VERSION 5.7 ;
  NOWIREEXTENSIONATPIN ON ;
  DIVIDERCHAR "/" ;
  BUSBITCHARS "[]" ;
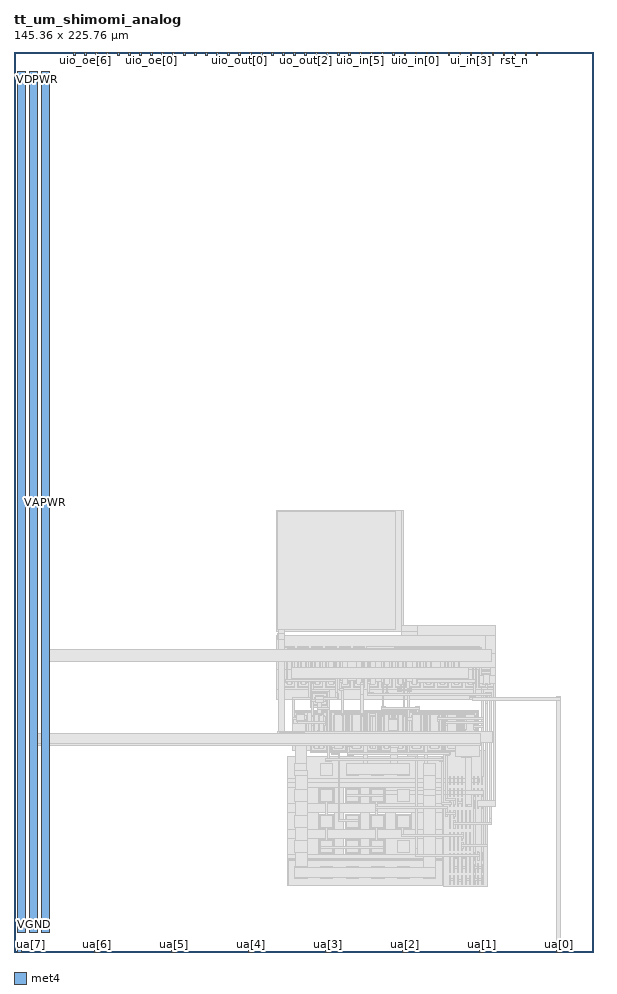
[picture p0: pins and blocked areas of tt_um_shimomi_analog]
MACRO tt_um_shimomi_analog
  CLASS BLOCK ;
  FOREIGN tt_um_shimomi_analog ;
  ORIGIN 0.000 0.000 ;
  SIZE 145.360 BY 225.760 ;
  PIN clk
    DIRECTION INPUT ;
    USE SIGNAL ;
    PORT
      LAYER met4 ;
        RECT 128.190 224.760 128.490 225.760 ;
    END
  END clk
  PIN ena
    DIRECTION INPUT ;
    USE SIGNAL ;
    PORT
      LAYER met4 ;
        RECT 130.950 224.760 131.250 225.760 ;
    END
  END ena
  PIN rst_n
    DIRECTION INPUT ;
    USE SIGNAL ;
    PORT
      LAYER met4 ;
        RECT 125.430 224.760 125.730 225.760 ;
    END
  END rst_n
  PIN ua[0]
    DIRECTION INOUT ;
    USE SIGNAL ;
    PORT
      LAYER met4 ;
        RECT 136.170 0.000 137.070 1.000 ;
    END
  END ua[0]
  PIN ua[1]
    DIRECTION INOUT ;
    USE SIGNAL ;
    PORT
      LAYER met4 ;
        RECT 116.850 0.000 117.750 1.000 ;
    END
  END ua[1]
  PIN ua[2]
    DIRECTION INOUT ;
    USE SIGNAL ;
    PORT
      LAYER met4 ;
        RECT 97.530 0.000 98.430 1.000 ;
    END
  END ua[2]
  PIN ua[3]
    DIRECTION INOUT ;
    USE SIGNAL ;
    PORT
      LAYER met4 ;
        RECT 78.210 0.000 79.110 1.000 ;
    END
  END ua[3]
  PIN ua[4]
    DIRECTION INOUT ;
    USE SIGNAL ;
    PORT
      LAYER met4 ;
        RECT 58.890 0.000 59.790 1.000 ;
    END
  END ua[4]
  PIN ua[5]
    DIRECTION INOUT ;
    USE SIGNAL ;
    PORT
      LAYER met4 ;
        RECT 39.570 0.000 40.470 1.000 ;
    END
  END ua[5]
  PIN ua[6]
    DIRECTION INOUT ;
    USE SIGNAL ;
    PORT
      LAYER met4 ;
        RECT 20.250 0.000 21.150 1.000 ;
    END
  END ua[6]
  PIN ua[7]
    DIRECTION INOUT ;
    USE SIGNAL ;
    PORT
      LAYER met4 ;
        RECT 0.930 0.000 1.830 1.000 ;
    END
  END ua[7]
  PIN ui_in[0]
    DIRECTION INPUT ;
    USE SIGNAL ;
    PORT
      LAYER met4 ;
        RECT 122.670 224.760 122.970 225.760 ;
    END
  END ui_in[0]
  PIN ui_in[1]
    DIRECTION INPUT ;
    USE SIGNAL ;
    PORT
      LAYER met4 ;
        RECT 119.910 224.760 120.210 225.760 ;
    END
  END ui_in[1]
  PIN ui_in[2]
    DIRECTION INPUT ;
    USE SIGNAL ;
    PORT
      LAYER met4 ;
        RECT 117.150 224.760 117.450 225.760 ;
    END
  END ui_in[2]
  PIN ui_in[3]
    DIRECTION INPUT ;
    USE SIGNAL ;
    PORT
      LAYER met4 ;
        RECT 114.390 224.760 114.690 225.760 ;
    END
  END ui_in[3]
  PIN ui_in[4]
    DIRECTION INPUT ;
    USE SIGNAL ;
    PORT
      LAYER met4 ;
        RECT 111.630 224.760 111.930 225.760 ;
    END
  END ui_in[4]
  PIN ui_in[5]
    DIRECTION INPUT ;
    USE SIGNAL ;
    PORT
      LAYER met4 ;
        RECT 108.870 224.760 109.170 225.760 ;
    END
  END ui_in[5]
  PIN ui_in[6]
    DIRECTION INPUT ;
    USE SIGNAL ;
    PORT
      LAYER met4 ;
        RECT 106.110 224.760 106.410 225.760 ;
    END
  END ui_in[6]
  PIN ui_in[7]
    DIRECTION INPUT ;
    USE SIGNAL ;
    PORT
      LAYER met4 ;
        RECT 103.350 224.760 103.650 225.760 ;
    END
  END ui_in[7]
  PIN uio_in[0]
    DIRECTION INPUT ;
    USE SIGNAL ;
    PORT
      LAYER met4 ;
        RECT 100.590 224.760 100.890 225.760 ;
    END
  END uio_in[0]
  PIN uio_in[1]
    DIRECTION INPUT ;
    USE SIGNAL ;
    PORT
      LAYER met4 ;
        RECT 97.830 224.760 98.130 225.760 ;
    END
  END uio_in[1]
  PIN uio_in[2]
    DIRECTION INPUT ;
    USE SIGNAL ;
    PORT
      LAYER met4 ;
        RECT 95.070 224.760 95.370 225.760 ;
    END
  END uio_in[2]
  PIN uio_in[3]
    DIRECTION INPUT ;
    USE SIGNAL ;
    PORT
      LAYER met4 ;
        RECT 92.310 224.760 92.610 225.760 ;
    END
  END uio_in[3]
  PIN uio_in[4]
    DIRECTION INPUT ;
    USE SIGNAL ;
    PORT
      LAYER met4 ;
        RECT 89.550 224.760 89.850 225.760 ;
    END
  END uio_in[4]
  PIN uio_in[5]
    DIRECTION INPUT ;
    USE SIGNAL ;
    PORT
      LAYER met4 ;
        RECT 86.790 224.760 87.090 225.760 ;
    END
  END uio_in[5]
  PIN uio_in[6]
    DIRECTION INPUT ;
    USE SIGNAL ;
    PORT
      LAYER met4 ;
        RECT 84.030 224.760 84.330 225.760 ;
    END
  END uio_in[6]
  PIN uio_in[7]
    DIRECTION INPUT ;
    USE SIGNAL ;
    PORT
      LAYER met4 ;
        RECT 81.270 224.760 81.570 225.760 ;
    END
  END uio_in[7]
  PIN uio_oe[0]
    DIRECTION OUTPUT ;
    USE SIGNAL ;
    PORT
      LAYER met4 ;
        RECT 34.350 224.760 34.650 225.760 ;
    END
  END uio_oe[0]
  PIN uio_oe[1]
    DIRECTION OUTPUT ;
    USE SIGNAL ;
    PORT
      LAYER met4 ;
        RECT 31.590 224.760 31.890 225.760 ;
    END
  END uio_oe[1]
  PIN uio_oe[2]
    DIRECTION OUTPUT ;
    USE SIGNAL ;
    PORT
      LAYER met4 ;
        RECT 28.830 224.760 29.130 225.760 ;
    END
  END uio_oe[2]
  PIN uio_oe[3]
    DIRECTION OUTPUT ;
    USE SIGNAL ;
    PORT
      LAYER met4 ;
        RECT 26.070 224.760 26.370 225.760 ;
    END
  END uio_oe[3]
  PIN uio_oe[4]
    DIRECTION OUTPUT ;
    USE SIGNAL ;
    PORT
      LAYER met4 ;
        RECT 23.310 224.760 23.610 225.760 ;
    END
  END uio_oe[4]
  PIN uio_oe[5]
    DIRECTION OUTPUT ;
    USE SIGNAL ;
    PORT
      LAYER met4 ;
        RECT 20.550 224.760 20.850 225.760 ;
    END
  END uio_oe[5]
  PIN uio_oe[6]
    DIRECTION OUTPUT ;
    USE SIGNAL ;
    PORT
      LAYER met4 ;
        RECT 17.790 224.760 18.090 225.760 ;
    END
  END uio_oe[6]
  PIN uio_oe[7]
    DIRECTION OUTPUT ;
    USE SIGNAL ;
    PORT
      LAYER met4 ;
        RECT 15.030 224.760 15.330 225.760 ;
    END
  END uio_oe[7]
  PIN uio_out[0]
    DIRECTION OUTPUT ;
    USE SIGNAL ;
    PORT
      LAYER met4 ;
        RECT 56.430 224.760 56.730 225.760 ;
    END
  END uio_out[0]
  PIN uio_out[1]
    DIRECTION OUTPUT ;
    USE SIGNAL ;
    PORT
      LAYER met4 ;
        RECT 53.670 224.760 53.970 225.760 ;
    END
  END uio_out[1]
  PIN uio_out[2]
    DIRECTION OUTPUT ;
    USE SIGNAL ;
    PORT
      LAYER met4 ;
        RECT 50.910 224.760 51.210 225.760 ;
    END
  END uio_out[2]
  PIN uio_out[3]
    DIRECTION OUTPUT ;
    USE SIGNAL ;
    PORT
      LAYER met4 ;
        RECT 48.150 224.760 48.450 225.760 ;
    END
  END uio_out[3]
  PIN uio_out[4]
    DIRECTION OUTPUT ;
    USE SIGNAL ;
    PORT
      LAYER met4 ;
        RECT 45.390 224.760 45.690 225.760 ;
    END
  END uio_out[4]
  PIN uio_out[5]
    DIRECTION OUTPUT ;
    USE SIGNAL ;
    PORT
      LAYER met4 ;
        RECT 42.630 224.760 42.930 225.760 ;
    END
  END uio_out[5]
  PIN uio_out[6]
    DIRECTION OUTPUT ;
    USE SIGNAL ;
    PORT
      LAYER met4 ;
        RECT 39.870 224.760 40.170 225.760 ;
    END
  END uio_out[6]
  PIN uio_out[7]
    DIRECTION OUTPUT ;
    USE SIGNAL ;
    PORT
      LAYER met4 ;
        RECT 37.110 224.760 37.410 225.760 ;
    END
  END uio_out[7]
  PIN uo_out[0]
    DIRECTION OUTPUT ;
    USE SIGNAL ;
    PORT
      LAYER met4 ;
        RECT 78.510 224.760 78.810 225.760 ;
    END
  END uo_out[0]
  PIN uo_out[1]
    DIRECTION OUTPUT ;
    USE SIGNAL ;
    PORT
      LAYER met4 ;
        RECT 75.750 224.760 76.050 225.760 ;
    END
  END uo_out[1]
  PIN uo_out[2]
    DIRECTION OUTPUT ;
    USE SIGNAL ;
    PORT
      LAYER met4 ;
        RECT 72.990 224.760 73.290 225.760 ;
    END
  END uo_out[2]
  PIN uo_out[3]
    DIRECTION OUTPUT ;
    USE SIGNAL ;
    PORT
      LAYER met4 ;
        RECT 70.230 224.760 70.530 225.760 ;
    END
  END uo_out[3]
  PIN uo_out[4]
    DIRECTION OUTPUT ;
    USE SIGNAL ;
    PORT
      LAYER met4 ;
        RECT 67.470 224.760 67.770 225.760 ;
    END
  END uo_out[4]
  PIN uo_out[5]
    DIRECTION OUTPUT ;
    USE SIGNAL ;
    PORT
      LAYER met4 ;
        RECT 64.710 224.760 65.010 225.760 ;
    END
  END uo_out[5]
  PIN uo_out[6]
    DIRECTION OUTPUT ;
    USE SIGNAL ;
    PORT
      LAYER met4 ;
        RECT 61.950 224.760 62.250 225.760 ;
    END
  END uo_out[6]
  PIN uo_out[7]
    DIRECTION OUTPUT ;
    USE SIGNAL ;
    PORT
      LAYER met4 ;
        RECT 59.190 224.760 59.490 225.760 ;
    END
  END uo_out[7]
  PIN VDPWR
    DIRECTION INOUT ;
    USE POWER ;
    PORT
      LAYER met4 ;
        RECT 1.000 5.000 3.000 220.760 ;
    END
  END VDPWR
  PIN VGND
    DIRECTION INOUT ;
    USE GROUND ;
    PORT
      LAYER met4 ;
        RECT 4.000 5.000 6.000 220.760 ;
    END
  END VGND
  PIN VAPWR
    DIRECTION INOUT ;
    USE POWER ;
    PORT
      LAYER met4 ;
        RECT 7.000 5.000 9.000 220.760 ;
    END
  END VAPWR
  OBS
      LAYER nwell ;
        RECT 65.750 70.900 120.750 79.430 ;
        RECT 65.750 65.930 120.830 70.900 ;
        RECT 65.750 63.430 120.750 65.930 ;
        RECT 74.250 61.430 78.830 63.430 ;
      LAYER pwell ;
        RECT 69.750 60.430 74.030 60.610 ;
        RECT 74.250 60.430 78.820 60.610 ;
        RECT 69.750 50.430 78.820 60.430 ;
        RECT 74.250 50.030 78.820 50.430 ;
        RECT 79.250 50.030 83.530 60.610 ;
        RECT 83.750 50.030 88.030 60.610 ;
        RECT 88.250 50.030 91.530 60.610 ;
        RECT 91.750 50.030 95.030 60.610 ;
        RECT 95.250 50.030 98.530 60.610 ;
        RECT 98.750 50.030 103.030 60.610 ;
        RECT 103.250 50.030 107.530 60.610 ;
        RECT 107.750 50.430 112.030 60.610 ;
        RECT 112.250 50.430 116.530 60.610 ;
        RECT 68.580 48.365 107.480 49.130 ;
        RECT 68.580 43.195 69.345 48.365 ;
        RECT 74.515 43.195 75.785 48.365 ;
        RECT 80.955 43.195 82.225 48.365 ;
        RECT 87.395 43.195 88.665 48.365 ;
        RECT 93.835 43.195 95.105 48.365 ;
        RECT 100.275 43.195 101.545 48.365 ;
        RECT 106.715 43.195 107.480 48.365 ;
        RECT 68.580 42.610 107.480 43.195 ;
        RECT 68.580 41.865 107.530 42.610 ;
        RECT 68.580 41.860 95.115 41.865 ;
        RECT 68.580 41.845 75.785 41.860 ;
        RECT 68.580 36.675 69.345 41.845 ;
        RECT 74.515 36.690 75.785 41.845 ;
        RECT 80.955 36.690 82.225 41.860 ;
        RECT 87.395 36.690 88.665 41.860 ;
        RECT 93.835 36.695 95.115 41.860 ;
        RECT 100.285 41.845 107.530 41.865 ;
        RECT 100.285 36.695 101.595 41.845 ;
        RECT 93.835 36.690 101.595 36.695 ;
        RECT 74.515 36.675 101.595 36.690 ;
        RECT 106.765 36.675 107.530 41.845 ;
        RECT 68.580 35.420 107.530 36.675 ;
        RECT 68.580 35.405 75.785 35.420 ;
        RECT 68.580 30.235 69.345 35.405 ;
        RECT 74.515 30.250 75.785 35.405 ;
        RECT 80.955 30.250 82.235 35.420 ;
        RECT 87.405 30.250 88.675 35.420 ;
        RECT 93.845 35.415 107.530 35.420 ;
        RECT 93.845 30.250 95.115 35.415 ;
        RECT 74.515 30.245 95.115 30.250 ;
        RECT 100.285 35.405 107.530 35.415 ;
        RECT 100.285 30.245 101.595 35.405 ;
        RECT 74.515 30.235 101.595 30.245 ;
        RECT 106.765 30.235 107.530 35.405 ;
        RECT 68.580 28.980 107.530 30.235 ;
        RECT 68.580 28.965 75.785 28.980 ;
        RECT 68.580 23.795 69.345 28.965 ;
        RECT 74.515 23.810 75.785 28.965 ;
        RECT 80.955 23.810 82.225 28.980 ;
        RECT 87.395 23.810 88.665 28.980 ;
        RECT 93.835 28.965 107.530 28.980 ;
        RECT 93.835 23.810 95.115 28.965 ;
        RECT 74.515 23.795 95.115 23.810 ;
        RECT 100.285 23.795 101.595 28.965 ;
        RECT 106.765 23.795 107.530 28.965 ;
        RECT 68.580 23.030 107.530 23.795 ;
        RECT 68.630 22.515 107.530 23.030 ;
        RECT 68.630 17.345 69.395 22.515 ;
        RECT 74.565 17.345 75.835 22.515 ;
        RECT 81.005 17.345 82.275 22.515 ;
        RECT 87.445 17.345 88.715 22.515 ;
        RECT 93.885 17.345 95.155 22.515 ;
        RECT 100.325 17.345 101.595 22.515 ;
        RECT 106.765 17.345 107.530 22.515 ;
        RECT 68.630 16.580 107.530 17.345 ;
        RECT 107.750 16.430 118.750 50.430 ;
      LAYER li1 ;
        RECT 67.640 76.340 70.440 76.510 ;
        RECT 67.640 66.490 67.810 76.340 ;
        RECT 68.540 75.650 69.540 75.820 ;
        RECT 68.310 67.395 68.480 75.435 ;
        RECT 69.600 67.395 69.770 75.435 ;
        RECT 68.540 67.010 69.540 67.180 ;
        RECT 70.270 66.490 70.440 76.340 ;
        RECT 67.640 66.320 70.440 66.490 ;
        RECT 71.140 76.340 73.940 76.510 ;
        RECT 71.140 66.490 71.310 76.340 ;
        RECT 72.040 75.650 73.040 75.820 ;
        RECT 71.810 67.395 71.980 75.435 ;
        RECT 73.100 67.395 73.270 75.435 ;
        RECT 72.040 67.010 73.040 67.180 ;
        RECT 73.770 66.490 73.940 76.340 ;
        RECT 71.140 66.320 73.940 66.490 ;
        RECT 74.640 76.340 77.440 76.510 ;
        RECT 74.640 66.490 74.810 76.340 ;
        RECT 75.540 75.650 76.540 75.820 ;
        RECT 75.310 67.395 75.480 75.435 ;
        RECT 76.600 67.395 76.770 75.435 ;
        RECT 75.540 67.010 76.540 67.180 ;
        RECT 77.270 66.490 77.440 76.340 ;
        RECT 74.640 66.320 77.440 66.490 ;
        RECT 78.140 76.340 80.940 76.510 ;
        RECT 78.140 66.490 78.310 76.340 ;
        RECT 79.040 75.650 80.040 75.820 ;
        RECT 78.810 67.395 78.980 75.435 ;
        RECT 80.100 67.395 80.270 75.435 ;
        RECT 79.040 67.010 80.040 67.180 ;
        RECT 80.770 66.490 80.940 76.340 ;
        RECT 78.140 66.320 80.940 66.490 ;
        RECT 81.640 76.340 84.440 76.510 ;
        RECT 81.640 66.490 81.810 76.340 ;
        RECT 82.540 75.650 83.540 75.820 ;
        RECT 82.310 67.395 82.480 75.435 ;
        RECT 83.600 67.395 83.770 75.435 ;
        RECT 82.540 67.010 83.540 67.180 ;
        RECT 84.270 66.490 84.440 76.340 ;
        RECT 81.640 66.320 84.440 66.490 ;
        RECT 85.140 76.340 87.940 76.510 ;
        RECT 85.140 66.490 85.310 76.340 ;
        RECT 86.040 75.650 87.040 75.820 ;
        RECT 85.810 67.395 85.980 75.435 ;
        RECT 87.100 67.395 87.270 75.435 ;
        RECT 86.040 67.010 87.040 67.180 ;
        RECT 87.770 66.490 87.940 76.340 ;
        RECT 85.140 66.320 87.940 66.490 ;
        RECT 88.640 76.340 91.440 76.510 ;
        RECT 88.640 66.490 88.810 76.340 ;
        RECT 89.540 75.650 90.540 75.820 ;
        RECT 89.310 67.395 89.480 75.435 ;
        RECT 90.600 67.395 90.770 75.435 ;
        RECT 89.540 67.010 90.540 67.180 ;
        RECT 91.270 66.490 91.440 76.340 ;
        RECT 88.640 66.320 91.440 66.490 ;
        RECT 92.140 76.340 94.940 76.510 ;
        RECT 92.140 66.490 92.310 76.340 ;
        RECT 93.040 75.650 94.040 75.820 ;
        RECT 92.810 67.395 92.980 75.435 ;
        RECT 94.100 67.395 94.270 75.435 ;
        RECT 93.040 67.010 94.040 67.180 ;
        RECT 94.770 66.490 94.940 76.340 ;
        RECT 92.140 66.320 94.940 66.490 ;
        RECT 95.640 76.340 98.440 76.510 ;
        RECT 95.640 66.490 95.810 76.340 ;
        RECT 96.540 75.650 97.540 75.820 ;
        RECT 96.310 67.395 96.480 75.435 ;
        RECT 97.600 67.395 97.770 75.435 ;
        RECT 96.540 67.010 97.540 67.180 ;
        RECT 98.270 66.490 98.440 76.340 ;
        RECT 95.640 66.320 98.440 66.490 ;
        RECT 99.140 76.340 101.940 76.510 ;
        RECT 99.140 66.490 99.310 76.340 ;
        RECT 100.040 75.650 101.040 75.820 ;
        RECT 99.810 67.395 99.980 75.435 ;
        RECT 101.100 67.395 101.270 75.435 ;
        RECT 100.040 67.010 101.040 67.180 ;
        RECT 101.770 66.490 101.940 76.340 ;
        RECT 99.140 66.320 101.940 66.490 ;
        RECT 102.640 76.340 105.440 76.510 ;
        RECT 102.640 66.490 102.810 76.340 ;
        RECT 103.540 75.650 104.540 75.820 ;
        RECT 103.310 67.395 103.480 75.435 ;
        RECT 104.600 67.395 104.770 75.435 ;
        RECT 103.540 67.010 104.540 67.180 ;
        RECT 105.270 66.490 105.440 76.340 ;
        RECT 102.640 66.320 105.440 66.490 ;
        RECT 106.140 76.340 108.940 76.510 ;
        RECT 106.140 66.490 106.310 76.340 ;
        RECT 107.040 75.650 108.040 75.820 ;
        RECT 106.810 67.395 106.980 75.435 ;
        RECT 108.100 67.395 108.270 75.435 ;
        RECT 107.040 67.010 108.040 67.180 ;
        RECT 108.770 66.490 108.940 76.340 ;
        RECT 106.140 66.320 108.940 66.490 ;
        RECT 109.640 76.340 112.440 76.510 ;
        RECT 109.640 66.490 109.810 76.340 ;
        RECT 110.540 75.650 111.540 75.820 ;
        RECT 110.310 67.395 110.480 75.435 ;
        RECT 111.600 67.395 111.770 75.435 ;
        RECT 110.540 67.010 111.540 67.180 ;
        RECT 112.270 66.490 112.440 76.340 ;
        RECT 109.640 66.320 112.440 66.490 ;
        RECT 113.140 76.340 115.940 76.510 ;
        RECT 113.140 66.490 113.310 76.340 ;
        RECT 114.040 75.650 115.040 75.820 ;
        RECT 113.810 67.395 113.980 75.435 ;
        RECT 115.100 67.395 115.270 75.435 ;
        RECT 114.040 67.010 115.040 67.180 ;
        RECT 115.770 66.490 115.940 76.340 ;
        RECT 113.140 66.320 115.940 66.490 ;
        RECT 116.640 70.340 120.440 70.510 ;
        RECT 116.640 66.490 116.810 70.340 ;
        RECT 117.540 69.650 119.540 69.820 ;
        RECT 117.310 67.395 117.480 69.435 ;
        RECT 119.600 67.395 119.770 69.435 ;
        RECT 120.270 69.430 120.440 70.340 ;
        RECT 120.050 67.530 120.550 69.430 ;
        RECT 117.540 67.010 119.540 67.180 ;
        RECT 120.270 66.490 120.440 67.530 ;
        RECT 116.640 66.320 120.440 66.490 ;
        RECT 74.640 64.840 78.440 65.010 ;
        RECT 74.640 61.990 74.810 64.840 ;
        RECT 75.540 64.150 77.540 64.320 ;
        RECT 75.310 62.895 75.480 63.935 ;
        RECT 77.600 62.895 77.770 63.935 ;
        RECT 75.540 62.510 77.540 62.680 ;
        RECT 78.270 61.990 78.440 64.840 ;
        RECT 74.640 61.820 78.440 61.990 ;
        RECT 73.750 60.370 74.750 60.430 ;
        RECT 69.990 60.200 78.580 60.370 ;
        RECT 69.990 57.440 70.160 60.200 ;
        RECT 70.890 59.510 72.890 59.680 ;
        RECT 70.660 58.300 70.830 59.340 ;
        RECT 72.950 58.300 73.120 59.340 ;
        RECT 70.890 57.960 72.890 58.130 ;
        RECT 73.620 57.440 74.750 60.200 ;
        RECT 75.390 59.510 76.390 59.680 ;
        RECT 76.680 59.510 77.680 59.680 ;
        RECT 69.990 57.270 74.750 57.440 ;
        RECT 73.750 55.430 74.750 57.270 ;
        RECT 74.490 55.230 74.660 55.430 ;
        RECT 74.250 52.430 74.660 55.230 ;
        RECT 74.490 50.440 74.660 52.430 ;
        RECT 75.160 51.300 75.330 59.340 ;
        RECT 76.450 51.300 76.620 59.340 ;
        RECT 77.740 51.300 77.910 59.340 ;
        RECT 75.390 50.960 76.390 51.130 ;
        RECT 76.680 50.960 77.680 51.130 ;
        RECT 78.410 50.440 78.580 60.200 ;
        RECT 74.490 50.270 78.580 50.440 ;
        RECT 79.490 60.200 83.290 60.370 ;
        RECT 79.490 50.440 79.660 60.200 ;
        RECT 80.390 59.510 82.390 59.680 ;
        RECT 80.160 51.300 80.330 59.340 ;
        RECT 82.450 51.300 82.620 59.340 ;
        RECT 83.120 55.130 83.290 60.200 ;
        RECT 83.990 60.200 87.790 60.370 ;
        RECT 83.990 55.130 84.160 60.200 ;
        RECT 84.890 59.510 86.890 59.680 ;
        RECT 83.120 52.530 84.160 55.130 ;
        RECT 80.390 50.960 82.390 51.130 ;
        RECT 83.120 50.440 83.290 52.530 ;
        RECT 79.490 50.270 83.290 50.440 ;
        RECT 83.990 50.440 84.160 52.530 ;
        RECT 84.660 51.300 84.830 59.340 ;
        RECT 86.950 51.300 87.120 59.340 ;
        RECT 87.620 55.230 87.790 60.200 ;
        RECT 88.490 60.200 91.290 60.370 ;
        RECT 88.490 55.230 88.660 60.200 ;
        RECT 89.390 59.510 90.390 59.680 ;
        RECT 87.620 52.530 88.660 55.230 ;
        RECT 84.890 50.960 86.890 51.130 ;
        RECT 87.620 50.440 87.790 52.530 ;
        RECT 83.990 50.270 87.790 50.440 ;
        RECT 88.490 50.440 88.660 52.530 ;
        RECT 89.160 51.300 89.330 59.340 ;
        RECT 90.450 51.300 90.620 59.340 ;
        RECT 91.120 55.230 91.290 60.200 ;
        RECT 91.990 60.200 94.790 60.370 ;
        RECT 91.990 55.230 92.160 60.200 ;
        RECT 92.890 59.510 93.890 59.680 ;
        RECT 91.120 52.430 92.160 55.230 ;
        RECT 89.390 50.960 90.390 51.130 ;
        RECT 91.120 50.440 91.290 52.430 ;
        RECT 88.490 50.270 91.290 50.440 ;
        RECT 91.990 50.440 92.160 52.430 ;
        RECT 92.660 51.300 92.830 59.340 ;
        RECT 93.950 58.330 94.120 59.340 ;
        RECT 94.620 58.330 94.790 60.200 ;
        RECT 95.490 60.200 98.290 60.370 ;
        RECT 95.490 58.330 95.660 60.200 ;
        RECT 96.390 59.510 97.390 59.680 ;
        RECT 96.160 58.330 96.330 59.340 ;
        RECT 93.950 52.730 96.330 58.330 ;
        RECT 93.950 51.300 94.120 52.730 ;
        RECT 92.890 50.960 93.890 51.130 ;
        RECT 94.620 50.440 94.790 52.730 ;
        RECT 91.990 50.270 94.790 50.440 ;
        RECT 95.490 50.440 95.660 52.730 ;
        RECT 96.160 51.300 96.330 52.730 ;
        RECT 97.450 51.300 97.620 59.340 ;
        RECT 96.390 50.960 97.390 51.130 ;
        RECT 98.120 50.440 98.290 60.200 ;
        RECT 95.490 50.270 98.290 50.440 ;
        RECT 98.990 60.200 102.790 60.370 ;
        RECT 98.990 50.440 99.160 60.200 ;
        RECT 99.890 59.510 101.890 59.680 ;
        RECT 99.660 51.300 99.830 59.340 ;
        RECT 101.950 51.300 102.120 59.340 ;
        RECT 102.620 55.230 102.790 60.200 ;
        RECT 103.490 60.200 107.290 60.370 ;
        RECT 103.490 55.230 103.660 60.200 ;
        RECT 104.390 59.510 106.390 59.680 ;
        RECT 102.620 52.530 103.660 55.230 ;
        RECT 99.890 50.960 101.890 51.130 ;
        RECT 102.620 50.440 102.790 52.530 ;
        RECT 98.990 50.270 102.790 50.440 ;
        RECT 103.490 50.440 103.660 52.530 ;
        RECT 104.160 51.300 104.330 59.340 ;
        RECT 106.450 51.300 106.620 59.340 ;
        RECT 104.390 50.960 106.390 51.130 ;
        RECT 107.120 50.440 107.290 60.200 ;
        RECT 103.490 50.270 107.290 50.440 ;
        RECT 107.990 60.200 111.790 60.370 ;
        RECT 107.990 50.440 108.160 60.200 ;
        RECT 108.890 59.510 110.890 59.680 ;
        RECT 108.660 51.300 108.830 59.340 ;
        RECT 110.950 55.230 111.120 59.340 ;
        RECT 111.620 55.230 111.790 60.200 ;
        RECT 112.490 60.200 116.290 60.370 ;
        RECT 112.490 55.230 112.660 60.200 ;
        RECT 113.390 59.510 115.390 59.680 ;
        RECT 113.160 55.230 113.330 59.340 ;
        RECT 110.950 52.530 113.330 55.230 ;
        RECT 110.950 51.300 111.120 52.530 ;
        RECT 108.890 50.960 110.890 51.130 ;
        RECT 111.620 50.440 111.790 52.530 ;
        RECT 107.990 50.270 111.790 50.440 ;
        RECT 112.490 50.440 112.660 52.530 ;
        RECT 113.160 51.300 113.330 52.530 ;
        RECT 115.450 51.300 115.620 59.340 ;
        RECT 116.120 55.330 116.290 60.200 ;
        RECT 116.120 52.430 116.450 55.330 ;
        RECT 113.390 50.960 115.390 51.130 ;
        RECT 116.120 50.440 116.290 52.430 ;
        RECT 112.490 50.270 116.290 50.440 ;
        RECT 68.710 43.430 107.350 49.000 ;
        RECT 109.250 43.430 109.600 44.090 ;
        RECT 110.250 43.430 110.600 44.090 ;
        RECT 111.250 43.430 111.600 44.090 ;
        RECT 112.250 43.430 112.600 44.090 ;
        RECT 113.250 43.430 113.600 44.090 ;
        RECT 114.250 43.430 114.600 44.090 ;
        RECT 115.250 43.430 115.600 44.090 ;
        RECT 116.250 43.430 116.600 44.090 ;
        RECT 68.710 42.430 116.750 43.430 ;
        RECT 68.710 41.320 107.400 42.430 ;
        RECT 109.250 41.930 109.600 42.430 ;
        RECT 110.250 41.930 110.600 42.430 ;
        RECT 111.250 41.930 111.600 42.430 ;
        RECT 112.250 41.930 112.600 42.430 ;
        RECT 113.250 41.930 113.600 42.430 ;
        RECT 114.250 41.930 114.600 42.430 ;
        RECT 115.250 41.930 115.600 42.430 ;
        RECT 116.250 41.930 116.600 42.430 ;
        RECT 117.250 41.930 117.600 44.090 ;
        RECT 68.710 37.230 76.325 41.320 ;
        RECT 76.635 37.540 80.105 41.010 ;
        RECT 80.415 37.230 82.765 41.320 ;
        RECT 83.075 37.540 86.545 41.010 ;
        RECT 86.855 37.230 89.205 41.320 ;
        RECT 89.515 37.540 92.985 41.010 ;
        RECT 93.295 40.430 107.400 41.320 ;
        RECT 109.250 40.430 109.600 41.090 ;
        RECT 110.250 40.430 110.600 41.090 ;
        RECT 111.250 40.430 111.600 41.090 ;
        RECT 112.250 40.430 112.600 41.090 ;
        RECT 113.250 40.430 113.600 41.090 ;
        RECT 114.250 40.430 114.600 41.090 ;
        RECT 115.250 40.430 115.600 41.090 ;
        RECT 116.250 40.430 116.600 41.090 ;
        RECT 117.250 40.430 117.600 41.090 ;
        RECT 93.295 39.430 117.750 40.430 ;
        RECT 93.295 37.230 107.400 39.430 ;
        RECT 109.250 38.930 109.600 39.430 ;
        RECT 110.250 38.930 110.600 39.430 ;
        RECT 111.250 38.930 111.600 39.430 ;
        RECT 112.250 38.930 112.600 39.430 ;
        RECT 113.250 38.930 113.600 39.430 ;
        RECT 114.250 38.930 114.600 39.430 ;
        RECT 68.710 34.880 107.400 37.230 ;
        RECT 109.250 36.430 109.600 38.590 ;
        RECT 110.250 36.430 110.600 38.590 ;
        RECT 111.250 37.630 111.600 38.590 ;
        RECT 112.250 37.630 112.600 38.590 ;
        RECT 111.250 37.330 112.600 37.630 ;
        RECT 111.250 36.430 111.600 37.330 ;
        RECT 112.250 36.430 112.600 37.330 ;
        RECT 113.250 36.430 113.600 38.590 ;
        RECT 114.250 36.430 114.600 38.590 ;
        RECT 68.710 30.790 76.325 34.880 ;
        RECT 76.635 31.100 80.105 34.570 ;
        RECT 80.415 30.790 82.775 34.880 ;
        RECT 83.085 31.100 86.555 34.570 ;
        RECT 86.865 30.790 89.215 34.880 ;
        RECT 93.305 34.875 107.400 34.880 ;
        RECT 89.525 31.100 92.995 34.570 ;
        RECT 93.305 30.790 95.655 34.875 ;
        RECT 95.965 31.095 99.435 34.565 ;
        RECT 68.710 30.785 95.655 30.790 ;
        RECT 99.745 30.785 107.400 34.875 ;
        RECT 109.250 33.430 109.600 35.590 ;
        RECT 110.250 33.430 110.600 35.590 ;
        RECT 111.250 33.430 111.600 35.590 ;
        RECT 112.250 33.430 112.600 35.590 ;
        RECT 113.250 33.430 113.600 35.590 ;
        RECT 114.250 33.430 114.600 35.590 ;
        RECT 109.250 33.090 109.550 33.430 ;
        RECT 111.250 33.090 111.550 33.430 ;
        RECT 112.250 33.090 112.550 33.430 ;
        RECT 113.250 33.090 113.550 33.430 ;
        RECT 114.250 33.090 114.550 33.430 ;
        RECT 109.250 30.930 109.600 33.090 ;
        RECT 110.250 30.930 110.600 33.090 ;
        RECT 111.250 30.930 111.600 33.090 ;
        RECT 112.250 30.930 112.600 33.090 ;
        RECT 113.250 30.930 113.600 33.090 ;
        RECT 114.250 30.930 114.600 33.090 ;
        RECT 68.710 28.440 107.400 30.785 ;
        RECT 68.710 24.350 76.325 28.440 ;
        RECT 76.635 24.660 80.105 28.130 ;
        RECT 80.415 24.350 82.765 28.440 ;
        RECT 83.075 24.660 86.545 28.130 ;
        RECT 86.855 24.350 89.205 28.440 ;
        RECT 89.515 24.660 92.985 28.130 ;
        RECT 93.295 24.350 107.400 28.440 ;
        RECT 109.250 27.930 109.600 30.090 ;
        RECT 110.250 27.930 110.600 30.090 ;
        RECT 111.250 27.930 111.600 30.090 ;
        RECT 112.250 27.930 112.600 30.090 ;
        RECT 113.250 27.930 113.600 30.090 ;
        RECT 114.250 27.930 114.600 30.090 ;
        RECT 109.250 27.590 109.550 27.930 ;
        RECT 110.250 27.590 110.550 27.930 ;
        RECT 111.250 27.590 111.550 27.930 ;
        RECT 113.250 27.590 113.550 27.930 ;
        RECT 114.250 27.590 114.550 27.930 ;
        RECT 109.250 25.430 109.600 27.590 ;
        RECT 110.250 25.430 110.600 27.590 ;
        RECT 111.250 25.430 111.600 27.590 ;
        RECT 112.250 25.430 112.600 27.590 ;
        RECT 113.250 25.430 113.600 27.590 ;
        RECT 114.250 25.430 114.600 27.590 ;
        RECT 68.710 23.335 107.400 24.350 ;
        RECT 68.710 23.160 107.405 23.335 ;
        RECT 68.715 23.010 107.405 23.160 ;
        RECT 68.760 16.710 107.400 23.010 ;
        RECT 109.250 22.430 109.600 24.590 ;
        RECT 110.250 23.730 110.600 24.590 ;
        RECT 111.250 23.730 111.600 24.590 ;
        RECT 110.250 23.430 111.600 23.730 ;
        RECT 110.250 22.430 110.600 23.430 ;
        RECT 111.250 22.430 111.600 23.430 ;
        RECT 112.250 23.730 112.600 24.590 ;
        RECT 113.250 23.730 113.600 24.590 ;
        RECT 112.250 23.430 113.600 23.730 ;
        RECT 112.250 22.430 112.600 23.430 ;
        RECT 113.250 22.430 113.600 23.430 ;
        RECT 114.250 22.430 114.600 24.590 ;
        RECT 109.250 22.090 109.550 22.430 ;
        RECT 114.250 22.090 114.550 22.430 ;
        RECT 109.250 19.930 109.600 22.090 ;
        RECT 110.250 21.330 110.600 22.090 ;
        RECT 111.250 21.330 111.600 22.090 ;
        RECT 110.250 20.830 111.600 21.330 ;
        RECT 110.250 19.930 110.600 20.830 ;
        RECT 111.250 19.930 111.600 20.830 ;
        RECT 112.250 21.330 112.600 22.090 ;
        RECT 113.250 21.330 113.600 22.090 ;
        RECT 112.250 20.830 113.600 21.330 ;
        RECT 112.250 19.930 112.600 20.830 ;
        RECT 113.250 19.930 113.600 20.830 ;
        RECT 114.250 19.930 114.600 22.090 ;
        RECT 115.250 21.330 115.750 39.430 ;
        RECT 116.250 38.930 116.600 39.430 ;
        RECT 116.250 35.930 116.600 38.090 ;
        RECT 116.250 22.930 116.600 25.090 ;
        RECT 116.250 21.330 116.600 22.090 ;
        RECT 117.250 21.330 117.750 39.430 ;
        RECT 115.250 20.930 117.750 21.330 ;
        RECT 109.250 18.330 109.600 19.090 ;
        RECT 110.250 18.330 110.600 19.090 ;
        RECT 109.250 17.830 110.600 18.330 ;
        RECT 109.250 16.930 109.600 17.830 ;
        RECT 110.250 16.930 110.600 17.830 ;
        RECT 111.250 18.230 111.600 19.090 ;
        RECT 112.250 18.230 112.600 19.090 ;
        RECT 111.250 17.730 112.600 18.230 ;
        RECT 111.250 16.930 111.600 17.730 ;
        RECT 112.250 16.930 112.600 17.730 ;
        RECT 113.250 18.330 113.600 19.090 ;
        RECT 114.250 18.330 114.600 19.090 ;
        RECT 113.250 17.830 114.600 18.330 ;
        RECT 113.250 16.930 113.600 17.830 ;
        RECT 114.250 16.930 114.600 17.830 ;
        RECT 115.250 18.330 115.750 20.930 ;
        RECT 116.250 19.930 116.600 20.930 ;
        RECT 116.250 18.330 116.600 19.090 ;
        RECT 117.250 18.330 117.750 20.930 ;
        RECT 115.250 17.830 117.750 18.330 ;
        RECT 115.250 16.930 115.750 17.830 ;
        RECT 116.250 16.930 116.600 17.830 ;
        RECT 117.250 16.930 117.750 17.830 ;
      LAYER met1 ;
        RECT 66.200 78.430 67.800 79.930 ;
        RECT 66.250 55.330 67.750 78.430 ;
        RECT 88.450 76.230 103.250 76.530 ;
        RECT 88.450 76.030 90.450 76.230 ;
        RECT 68.550 75.850 90.450 76.030 ;
        RECT 100.150 76.030 103.250 76.230 ;
        RECT 100.150 75.850 114.950 76.030 ;
        RECT 116.200 75.930 117.300 76.430 ;
        RECT 68.550 75.730 90.520 75.850 ;
        RECT 68.560 75.620 69.520 75.730 ;
        RECT 72.060 75.620 73.020 75.730 ;
        RECT 68.280 68.430 68.510 75.415 ;
        RECT 68.000 67.730 68.510 68.430 ;
        RECT 68.280 67.415 68.510 67.730 ;
        RECT 69.570 71.330 69.800 75.415 ;
        RECT 71.780 71.330 72.010 75.415 ;
        RECT 69.570 68.730 72.010 71.330 ;
        RECT 69.570 67.415 69.800 68.730 ;
        RECT 71.780 67.415 72.010 68.730 ;
        RECT 73.070 68.530 73.300 75.415 ;
        RECT 73.070 67.530 73.600 68.530 ;
        RECT 73.070 67.415 73.300 67.530 ;
        RECT 68.560 66.980 69.520 67.210 ;
        RECT 72.060 66.980 73.020 67.210 ;
        RECT 73.750 63.930 74.250 75.730 ;
        RECT 75.560 75.620 76.520 75.730 ;
        RECT 79.060 75.620 80.020 75.730 ;
        RECT 82.560 75.620 83.520 75.730 ;
        RECT 86.060 75.620 87.020 75.730 ;
        RECT 89.560 75.620 90.520 75.730 ;
        RECT 93.060 75.620 94.020 75.850 ;
        RECT 96.560 75.620 97.520 75.850 ;
        RECT 100.060 75.730 115.020 75.850 ;
        RECT 100.060 75.620 101.020 75.730 ;
        RECT 103.560 75.620 104.520 75.730 ;
        RECT 107.060 75.620 108.020 75.730 ;
        RECT 110.560 75.620 111.520 75.730 ;
        RECT 114.060 75.620 115.020 75.730 ;
        RECT 75.280 68.530 75.510 75.415 ;
        RECT 74.700 67.530 75.510 68.530 ;
        RECT 74.750 67.415 75.510 67.530 ;
        RECT 76.570 71.330 76.800 75.415 ;
        RECT 78.780 71.330 79.010 75.415 ;
        RECT 76.570 68.730 79.010 71.330 ;
        RECT 76.570 67.415 76.800 68.730 ;
        RECT 78.780 67.415 79.010 68.730 ;
        RECT 80.070 68.430 80.300 75.415 ;
        RECT 80.700 68.930 81.800 70.930 ;
        RECT 80.070 67.730 80.600 68.430 ;
        RECT 80.070 67.415 80.300 67.730 ;
        RECT 74.750 67.330 75.350 67.415 ;
        RECT 74.750 65.930 75.250 67.330 ;
        RECT 75.560 66.980 76.520 67.210 ;
        RECT 79.060 66.980 80.020 67.210 ;
        RECT 74.750 65.430 79.250 65.930 ;
        RECT 75.560 64.120 77.520 64.350 ;
        RECT 69.750 63.430 74.250 63.930 ;
        RECT 77.700 63.915 78.300 63.930 ;
        RECT 69.750 58.930 70.250 63.430 ;
        RECT 75.280 63.230 75.510 63.915 ;
        RECT 74.750 62.915 75.510 63.230 ;
        RECT 77.570 62.930 78.300 63.915 ;
        RECT 77.570 62.915 77.800 62.930 ;
        RECT 74.750 62.830 75.350 62.915 ;
        RECT 70.910 59.480 72.870 59.710 ;
        RECT 74.750 59.330 75.050 62.830 ;
        RECT 75.560 62.480 77.520 62.710 ;
        RECT 76.250 61.430 77.250 62.480 ;
        RECT 78.750 61.430 79.250 65.430 ;
        RECT 80.750 64.930 81.250 68.930 ;
        RECT 82.280 68.180 82.510 75.415 ;
        RECT 81.635 67.685 82.510 68.180 ;
        RECT 81.635 66.210 82.130 67.685 ;
        RECT 82.280 67.415 82.510 67.685 ;
        RECT 83.570 74.830 83.800 75.415 ;
        RECT 85.780 74.830 86.010 75.415 ;
        RECT 83.570 68.030 86.010 74.830 ;
        RECT 83.570 67.415 83.800 68.030 ;
        RECT 85.780 67.415 86.010 68.030 ;
        RECT 87.070 67.580 87.300 75.415 ;
        RECT 89.280 67.930 89.510 75.415 ;
        RECT 86.925 67.555 87.300 67.580 ;
        RECT 86.925 67.210 87.575 67.555 ;
        RECT 82.560 66.980 83.520 67.210 ;
        RECT 86.060 66.980 87.575 67.210 ;
        RECT 81.635 65.715 82.750 66.210 ;
        RECT 80.700 63.430 81.300 64.930 ;
        RECT 76.250 60.930 79.250 61.430 ;
        RECT 76.250 59.830 77.250 60.930 ;
        RECT 76.050 59.710 77.250 59.830 ;
        RECT 75.410 59.530 77.660 59.710 ;
        RECT 75.410 59.480 76.370 59.530 ;
        RECT 76.700 59.480 77.660 59.530 ;
        RECT 76.750 59.430 77.250 59.480 ;
        RECT 74.750 59.320 75.250 59.330 ;
        RECT 70.630 58.930 70.860 59.320 ;
        RECT 69.750 58.430 70.860 58.930 ;
        RECT 70.630 58.320 70.860 58.430 ;
        RECT 72.920 59.230 73.150 59.320 ;
        RECT 72.920 58.320 73.350 59.230 ;
        RECT 74.750 58.930 75.360 59.320 ;
        RECT 70.910 57.930 72.870 58.160 ;
        RECT 71.000 57.430 72.600 57.930 ;
        RECT 73.050 55.330 73.350 58.320 ;
        RECT 74.700 56.930 75.360 58.930 ;
        RECT 66.200 52.430 73.400 55.330 ;
        RECT 74.220 55.230 74.680 55.290 ;
        RECT 74.200 52.430 74.700 55.230 ;
        RECT 66.250 51.930 67.750 52.430 ;
        RECT 70.550 47.305 73.350 52.430 ;
        RECT 74.220 52.370 74.680 52.430 ;
        RECT 75.130 51.320 75.360 56.930 ;
        RECT 76.420 55.430 76.650 59.320 ;
        RECT 77.710 58.930 77.940 59.320 ;
        RECT 77.700 56.930 78.300 58.930 ;
        RECT 76.200 51.930 76.800 55.430 ;
        RECT 76.420 51.320 76.650 51.930 ;
        RECT 77.710 51.320 77.940 56.930 ;
        RECT 75.410 50.930 76.370 51.160 ;
        RECT 76.700 50.930 77.660 51.160 ;
        RECT 78.750 48.430 79.250 60.930 ;
        RECT 82.255 59.730 82.750 65.715 ;
        RECT 87.025 64.500 87.575 66.980 ;
        RECT 88.750 67.415 89.510 67.930 ;
        RECT 90.570 74.830 90.800 75.415 ;
        RECT 90.570 67.930 92.300 74.830 ;
        RECT 90.570 67.415 90.800 67.930 ;
        RECT 92.780 67.630 93.010 75.415 ;
        RECT 92.550 67.415 93.010 67.630 ;
        RECT 94.070 75.130 94.300 75.415 ;
        RECT 96.280 75.130 96.510 75.415 ;
        RECT 94.070 73.230 96.510 75.130 ;
        RECT 94.070 67.415 94.300 73.230 ;
        RECT 96.280 67.415 96.510 73.230 ;
        RECT 97.570 67.630 97.800 75.415 ;
        RECT 99.780 74.830 100.010 75.415 ;
        RECT 98.300 67.930 100.010 74.830 ;
        RECT 97.570 67.415 97.950 67.630 ;
        RECT 99.780 67.415 100.010 67.930 ;
        RECT 101.070 68.330 101.300 75.415 ;
        RECT 103.280 68.330 103.510 75.415 ;
        RECT 101.070 67.630 103.510 68.330 ;
        RECT 101.070 67.415 101.300 67.630 ;
        RECT 103.280 67.415 103.510 67.630 ;
        RECT 104.570 74.830 104.800 75.415 ;
        RECT 106.780 74.830 107.010 75.415 ;
        RECT 104.570 68.730 107.010 74.830 ;
        RECT 104.570 67.415 104.800 68.730 ;
        RECT 106.780 67.415 107.010 68.730 ;
        RECT 108.070 68.330 108.300 75.415 ;
        RECT 110.280 68.330 110.510 75.415 ;
        RECT 108.070 67.630 110.510 68.330 ;
        RECT 108.070 67.415 108.300 67.630 ;
        RECT 110.280 67.415 110.510 67.630 ;
        RECT 111.570 74.830 111.800 75.415 ;
        RECT 113.780 74.830 114.010 75.415 ;
        RECT 111.570 68.730 114.010 74.830 ;
        RECT 111.570 67.415 111.800 68.730 ;
        RECT 113.780 67.415 114.010 68.730 ;
        RECT 115.070 68.330 115.300 75.415 ;
        RECT 116.750 69.430 117.250 75.930 ;
        RECT 117.560 69.620 119.520 69.850 ;
        RECT 120.020 69.430 120.580 69.490 ;
        RECT 115.070 67.630 115.900 68.330 ;
        RECT 115.070 67.415 115.750 67.630 ;
        RECT 116.700 67.430 117.800 69.430 ;
        RECT 119.200 67.930 120.580 69.430 ;
        RECT 119.200 67.430 120.750 67.930 ;
        RECT 117.280 67.415 117.510 67.430 ;
        RECT 88.750 67.330 89.350 67.415 ;
        RECT 92.550 67.380 92.975 67.415 ;
        RECT 88.750 64.930 89.250 67.330 ;
        RECT 89.560 66.980 90.520 67.210 ;
        RECT 82.255 59.710 86.750 59.730 ;
        RECT 87.030 59.715 87.570 64.500 ;
        RECT 88.700 64.430 90.300 64.930 ;
        RECT 92.550 61.430 92.750 67.380 ;
        RECT 93.060 66.980 94.020 67.210 ;
        RECT 96.560 66.980 97.520 67.210 ;
        RECT 93.450 64.930 93.650 66.980 ;
        RECT 96.950 65.930 97.250 66.980 ;
        RECT 96.200 65.430 97.300 65.930 ;
        RECT 96.950 65.230 97.250 65.430 ;
        RECT 93.200 64.430 93.900 64.930 ;
        RECT 92.200 60.930 93.300 61.430 ;
        RECT 80.410 59.530 86.870 59.710 ;
        RECT 87.030 59.630 87.575 59.715 ;
        RECT 80.410 59.480 82.750 59.530 ;
        RECT 84.910 59.480 86.870 59.530 ;
        RECT 80.130 52.130 80.360 59.320 ;
        RECT 82.255 59.270 82.750 59.480 ;
        RECT 87.120 59.320 87.575 59.630 ;
        RECT 89.150 59.320 90.650 59.730 ;
        RECT 79.650 51.780 80.360 52.130 ;
        RECT 79.660 51.320 80.360 51.780 ;
        RECT 82.420 51.320 82.650 59.270 ;
        RECT 83.120 55.130 84.080 55.190 ;
        RECT 83.100 52.530 84.100 55.130 ;
        RECT 83.120 52.470 84.080 52.530 ;
        RECT 84.630 51.930 84.860 59.320 ;
        RECT 83.750 51.430 84.860 51.930 ;
        RECT 79.660 51.280 80.200 51.320 ;
        RECT 79.660 49.850 79.995 51.280 ;
        RECT 80.410 50.930 82.370 51.160 ;
        RECT 83.750 49.930 84.250 51.430 ;
        RECT 84.630 51.320 84.860 51.430 ;
        RECT 86.920 59.025 87.575 59.320 ;
        RECT 89.130 59.030 90.650 59.320 ;
        RECT 92.550 59.320 92.750 60.930 ;
        RECT 97.750 59.830 97.950 67.415 ;
        RECT 100.060 66.980 101.020 67.210 ;
        RECT 103.560 66.980 104.520 67.210 ;
        RECT 107.060 66.980 108.020 67.210 ;
        RECT 110.560 66.980 111.520 67.210 ;
        RECT 114.060 66.980 115.020 67.210 ;
        RECT 98.700 65.430 99.800 65.930 ;
        RECT 93.250 59.710 97.950 59.830 ;
        RECT 92.910 59.530 97.950 59.710 ;
        RECT 92.910 59.480 93.870 59.530 ;
        RECT 96.410 59.480 97.370 59.530 ;
        RECT 97.750 59.330 97.950 59.530 ;
        RECT 97.600 59.320 97.950 59.330 ;
        RECT 92.550 59.030 92.860 59.320 ;
        RECT 86.920 51.320 87.150 59.025 ;
        RECT 87.720 55.230 88.680 55.290 ;
        RECT 87.700 54.230 88.700 55.230 ;
        RECT 87.700 52.530 88.750 54.230 ;
        RECT 87.720 52.470 88.750 52.530 ;
        RECT 84.910 50.930 86.870 51.160 ;
        RECT 79.660 49.515 81.715 49.850 ;
        RECT 78.200 47.930 79.800 48.430 ;
        RECT 70.405 45.530 73.455 47.305 ;
        RECT 70.405 44.255 73.550 45.530 ;
        RECT 76.845 44.255 79.895 47.305 ;
        RECT 70.650 40.785 73.550 44.255 ;
        RECT 70.405 37.735 73.550 40.785 ;
        RECT 76.845 37.750 79.895 40.800 ;
        RECT 70.650 34.345 73.550 37.735 ;
        RECT 78.250 34.360 78.750 37.750 ;
        RECT 70.405 31.295 73.550 34.345 ;
        RECT 76.845 31.310 79.895 34.360 ;
        RECT 81.385 33.140 81.705 49.515 ;
        RECT 83.700 49.430 85.300 49.930 ;
        RECT 83.285 47.230 86.335 47.305 ;
        RECT 87.750 47.230 88.750 52.470 ;
        RECT 89.130 51.320 89.360 59.030 ;
        RECT 90.050 55.230 90.650 59.030 ;
        RECT 91.120 55.230 92.080 55.290 ;
        RECT 90.000 52.630 90.700 55.230 ;
        RECT 90.050 51.160 90.650 52.630 ;
        RECT 91.100 52.430 92.100 55.230 ;
        RECT 91.120 52.370 92.080 52.430 ;
        RECT 92.630 51.320 92.860 59.030 ;
        RECT 93.920 58.430 94.150 59.320 ;
        RECT 96.130 58.430 96.360 59.320 ;
        RECT 93.920 52.430 96.360 58.430 ;
        RECT 93.920 51.320 94.150 52.430 ;
        RECT 94.350 51.320 96.360 52.430 ;
        RECT 97.420 59.030 97.950 59.320 ;
        RECT 97.420 51.320 97.650 59.030 ;
        RECT 98.750 58.930 99.250 65.430 ;
        RECT 115.250 63.930 115.750 67.415 ;
        RECT 118.250 67.210 118.750 67.430 ;
        RECT 119.570 67.415 119.800 67.430 ;
        RECT 117.560 66.980 119.520 67.210 ;
        RECT 118.250 66.430 118.750 66.980 ;
        RECT 117.250 65.930 118.750 66.430 ;
        RECT 114.200 63.430 115.800 63.930 ;
        RECT 100.700 60.930 101.800 61.430 ;
        RECT 100.850 60.030 101.350 60.930 ;
        RECT 100.150 59.710 115.450 60.030 ;
        RECT 99.910 59.630 115.450 59.710 ;
        RECT 99.910 59.480 101.870 59.630 ;
        RECT 104.410 59.480 106.370 59.630 ;
        RECT 108.910 59.480 110.870 59.630 ;
        RECT 113.410 59.480 115.370 59.630 ;
        RECT 99.630 58.930 99.860 59.320 ;
        RECT 98.750 58.130 99.860 58.930 ;
        RECT 98.750 52.930 99.250 58.130 ;
        RECT 99.630 52.930 99.860 58.130 ;
        RECT 98.750 52.430 99.860 52.930 ;
        RECT 89.410 51.030 90.650 51.160 ;
        RECT 89.410 50.930 90.370 51.030 ;
        RECT 92.910 50.930 93.870 51.160 ;
        RECT 94.350 47.330 96.150 51.320 ;
        RECT 96.410 50.930 97.370 51.160 ;
        RECT 98.750 49.430 99.250 52.430 ;
        RECT 99.630 51.320 99.860 52.430 ;
        RECT 101.920 55.230 102.150 59.320 ;
        RECT 104.130 58.330 104.360 59.320 ;
        RECT 106.420 58.930 106.650 59.320 ;
        RECT 104.130 55.730 104.400 58.330 ;
        RECT 106.200 57.930 106.800 58.930 ;
        RECT 108.630 57.930 108.860 59.320 ;
        RECT 102.620 55.230 103.580 55.290 ;
        RECT 104.130 55.230 104.360 55.730 ;
        RECT 101.920 52.530 104.360 55.230 ;
        RECT 101.920 51.320 102.150 52.530 ;
        RECT 102.620 52.470 103.650 52.530 ;
        RECT 99.910 50.930 101.870 51.160 ;
        RECT 98.750 48.930 101.250 49.430 ;
        RECT 94.350 47.305 96.250 47.330 ;
        RECT 89.725 47.230 92.775 47.305 ;
        RECT 94.350 47.230 99.215 47.305 ;
        RECT 83.285 44.530 99.215 47.230 ;
        RECT 83.285 44.255 86.335 44.530 ;
        RECT 89.725 44.255 92.775 44.530 ;
        RECT 96.165 44.255 99.215 44.530 ;
        RECT 83.285 39.430 86.335 40.800 ;
        RECT 89.725 39.430 92.775 40.800 ;
        RECT 83.285 38.930 92.775 39.430 ;
        RECT 83.285 37.750 86.335 38.930 ;
        RECT 89.725 37.750 92.775 38.930 ;
        RECT 96.175 37.755 99.225 40.805 ;
        RECT 90.750 36.930 91.250 37.750 ;
        RECT 90.700 35.430 91.300 36.930 ;
        RECT 90.750 34.360 91.250 35.430 ;
        RECT 83.295 33.140 86.345 34.360 ;
        RECT 81.385 32.820 86.345 33.140 ;
        RECT 83.295 31.310 86.345 32.820 ;
        RECT 89.735 31.310 92.785 34.360 ;
        RECT 70.650 27.905 73.550 31.295 ;
        RECT 78.250 27.920 78.750 31.310 ;
        RECT 90.750 27.920 91.250 31.310 ;
        RECT 96.175 31.305 99.225 34.355 ;
        RECT 97.250 29.430 97.750 31.305 ;
        RECT 97.200 28.930 98.800 29.430 ;
        RECT 70.405 24.855 73.550 27.905 ;
        RECT 76.845 26.430 79.895 27.920 ;
        RECT 83.285 26.430 86.335 27.920 ;
        RECT 89.725 26.430 92.775 27.920 ;
        RECT 76.845 25.930 92.775 26.430 ;
        RECT 76.845 24.870 79.895 25.930 ;
        RECT 83.285 24.870 86.335 25.930 ;
        RECT 89.725 24.870 92.775 25.930 ;
        RECT 96.175 24.855 99.225 27.905 ;
        RECT 100.750 25.930 101.250 48.930 ;
        RECT 102.950 47.305 103.650 52.470 ;
        RECT 104.130 51.320 104.360 52.530 ;
        RECT 106.420 51.320 106.650 57.930 ;
        RECT 108.200 56.930 108.860 57.930 ;
        RECT 108.630 51.320 108.860 56.930 ;
        RECT 110.920 55.230 111.150 59.320 ;
        RECT 113.130 58.430 113.360 59.320 ;
        RECT 113.130 55.830 113.400 58.430 ;
        RECT 115.420 56.930 115.650 59.320 ;
        RECT 115.200 55.930 115.800 56.930 ;
        RECT 111.720 55.230 112.580 55.290 ;
        RECT 113.130 55.230 113.360 55.830 ;
        RECT 110.920 52.530 113.360 55.230 ;
        RECT 110.920 51.320 111.150 52.530 ;
        RECT 113.130 51.320 113.360 52.530 ;
        RECT 115.420 51.320 115.650 55.930 ;
        RECT 116.120 55.330 116.480 55.390 ;
        RECT 116.100 52.430 116.500 55.330 ;
        RECT 116.120 52.370 116.480 52.430 ;
        RECT 104.410 50.930 106.370 51.160 ;
        RECT 108.910 50.930 110.870 51.160 ;
        RECT 113.410 50.930 115.370 51.160 ;
        RECT 108.200 49.430 109.400 49.930 ;
        RECT 106.700 47.930 107.800 48.430 ;
        RECT 102.605 44.255 105.655 47.305 ;
        RECT 102.650 40.785 105.650 44.255 ;
        RECT 102.650 39.330 105.705 40.785 ;
        RECT 70.650 21.455 73.550 24.855 ;
        RECT 100.700 23.930 101.300 25.930 ;
        RECT 70.455 21.130 73.550 21.455 ;
        RECT 76.895 21.130 79.945 21.455 ;
        RECT 83.335 21.130 86.385 21.455 ;
        RECT 89.775 21.130 92.825 21.455 ;
        RECT 96.215 21.130 99.265 21.455 ;
        RECT 102.650 21.130 105.750 39.330 ;
        RECT 107.250 37.430 107.750 47.930 ;
        RECT 108.250 39.430 108.750 49.430 ;
        RECT 112.200 48.930 114.800 49.930 ;
        RECT 109.300 41.955 109.550 44.060 ;
        RECT 110.300 41.955 110.550 44.060 ;
        RECT 111.300 41.955 111.550 44.060 ;
        RECT 112.300 41.955 112.550 44.060 ;
        RECT 108.200 37.930 108.800 39.430 ;
        RECT 109.300 38.960 109.550 41.065 ;
        RECT 110.300 38.960 110.550 41.065 ;
        RECT 111.300 38.960 111.550 41.065 ;
        RECT 112.300 38.960 112.550 41.065 ;
        RECT 113.250 40.430 114.750 48.930 ;
        RECT 115.300 41.955 115.550 44.060 ;
        RECT 116.300 41.955 116.550 44.060 ;
        RECT 117.250 43.930 117.750 65.930 ;
        RECT 118.200 64.430 119.800 64.930 ;
        RECT 118.200 62.430 118.800 63.930 ;
        RECT 117.300 41.955 117.550 43.930 ;
        RECT 115.300 40.430 115.550 41.065 ;
        RECT 116.300 40.430 116.550 41.065 ;
        RECT 117.300 40.430 117.550 41.065 ;
        RECT 113.250 39.430 117.750 40.430 ;
        RECT 109.300 37.430 109.550 38.560 ;
        RECT 110.300 38.430 110.550 38.560 ;
        RECT 107.250 36.930 109.750 37.430 ;
        RECT 110.200 36.930 110.800 38.430 ;
        RECT 111.300 37.630 111.550 38.560 ;
        RECT 112.300 37.630 112.550 38.560 ;
        RECT 111.300 37.330 112.550 37.630 ;
        RECT 109.300 36.455 109.550 36.930 ;
        RECT 110.300 36.455 110.550 36.930 ;
        RECT 111.300 36.455 111.550 37.330 ;
        RECT 112.300 36.455 112.550 37.330 ;
        RECT 113.250 36.930 114.750 39.430 ;
        RECT 115.300 38.960 115.550 39.430 ;
        RECT 116.300 38.960 116.550 39.430 ;
        RECT 117.300 38.960 117.550 39.430 ;
        RECT 113.300 36.455 113.550 36.930 ;
        RECT 113.750 36.430 114.750 36.930 ;
        RECT 115.300 35.955 115.550 38.060 ;
        RECT 116.300 37.930 116.550 38.060 ;
        RECT 116.200 36.430 116.800 37.930 ;
        RECT 116.300 35.955 116.550 36.430 ;
        RECT 117.300 35.955 117.550 38.060 ;
        RECT 108.200 33.930 108.800 35.430 ;
        RECT 109.300 33.460 109.550 35.565 ;
        RECT 110.300 35.430 110.550 35.565 ;
        RECT 110.200 33.930 110.800 35.430 ;
        RECT 110.300 33.460 110.550 33.930 ;
        RECT 111.300 33.830 111.550 35.565 ;
        RECT 112.300 33.930 112.550 35.565 ;
        RECT 109.300 30.955 109.550 33.060 ;
        RECT 110.300 32.930 110.550 33.060 ;
        RECT 110.200 30.930 110.800 32.930 ;
        RECT 111.250 32.730 111.550 33.830 ;
        RECT 112.250 32.830 112.550 33.930 ;
        RECT 113.300 33.830 113.550 35.565 ;
        RECT 111.300 30.955 111.550 32.730 ;
        RECT 112.300 30.955 112.550 32.830 ;
        RECT 113.250 32.730 113.550 33.830 ;
        RECT 114.300 33.460 114.550 35.565 ;
        RECT 113.300 30.955 113.550 32.730 ;
        RECT 114.300 30.955 114.550 33.060 ;
        RECT 109.300 27.960 109.550 30.065 ;
        RECT 110.300 28.330 110.550 30.065 ;
        RECT 111.300 28.330 111.550 30.065 ;
        RECT 112.300 29.930 112.550 30.065 ;
        RECT 112.200 28.430 112.800 29.930 ;
        RECT 109.300 25.455 109.550 27.560 ;
        RECT 110.250 27.230 110.550 28.330 ;
        RECT 111.250 27.230 111.550 28.330 ;
        RECT 112.300 27.960 112.550 28.430 ;
        RECT 113.300 28.330 113.550 30.065 ;
        RECT 112.300 27.430 112.550 27.560 ;
        RECT 110.300 25.455 110.550 27.230 ;
        RECT 111.300 25.455 111.550 27.230 ;
        RECT 112.200 25.930 112.800 27.430 ;
        RECT 113.250 27.230 113.550 28.330 ;
        RECT 114.300 27.960 114.550 30.065 ;
        RECT 112.300 25.455 112.550 25.930 ;
        RECT 113.300 25.455 113.550 27.230 ;
        RECT 114.300 25.455 114.550 27.560 ;
        RECT 118.250 26.930 118.750 62.430 ;
        RECT 119.250 33.430 119.750 64.430 ;
        RECT 120.250 37.930 120.750 67.430 ;
        RECT 120.200 36.430 120.800 37.930 ;
        RECT 119.200 31.930 119.800 33.430 ;
        RECT 117.700 26.430 118.800 26.930 ;
        RECT 109.300 22.460 109.550 24.565 ;
        RECT 110.300 23.730 110.550 24.565 ;
        RECT 111.300 23.730 111.550 24.565 ;
        RECT 110.300 23.430 111.550 23.730 ;
        RECT 110.300 22.460 110.550 23.430 ;
        RECT 111.300 22.460 111.550 23.430 ;
        RECT 112.300 23.730 112.550 24.565 ;
        RECT 113.300 23.730 113.550 24.565 ;
        RECT 112.300 23.430 113.550 23.730 ;
        RECT 112.300 22.460 112.550 23.430 ;
        RECT 113.300 22.460 113.550 23.430 ;
        RECT 114.300 22.460 114.550 24.565 ;
        RECT 115.300 22.960 115.550 25.065 ;
        RECT 116.300 24.930 116.550 25.065 ;
        RECT 116.200 22.930 116.800 24.930 ;
        RECT 117.300 22.960 117.550 25.065 ;
        RECT 70.455 18.730 105.850 21.130 ;
        RECT 109.300 19.955 109.550 22.060 ;
        RECT 110.300 19.955 110.550 22.060 ;
        RECT 111.300 19.955 111.550 22.060 ;
        RECT 112.300 19.955 112.550 22.060 ;
        RECT 113.300 19.955 113.550 22.060 ;
        RECT 114.300 19.955 114.550 22.060 ;
        RECT 115.300 19.955 115.550 22.060 ;
        RECT 116.300 19.955 116.550 22.060 ;
        RECT 117.300 19.955 117.550 22.060 ;
        RECT 70.455 18.405 73.505 18.730 ;
        RECT 76.895 18.405 79.945 18.730 ;
        RECT 83.335 18.405 86.385 18.730 ;
        RECT 89.775 18.405 92.825 18.730 ;
        RECT 96.215 18.405 99.265 18.730 ;
        RECT 102.650 18.630 105.750 18.730 ;
        RECT 102.655 18.405 105.705 18.630 ;
        RECT 109.300 16.960 109.550 19.065 ;
        RECT 110.300 16.960 110.550 19.065 ;
        RECT 111.300 16.960 111.550 19.065 ;
        RECT 112.300 16.960 112.550 19.065 ;
        RECT 113.300 16.960 113.550 19.065 ;
        RECT 114.300 16.960 114.550 19.065 ;
        RECT 115.300 16.960 115.550 19.065 ;
        RECT 116.300 16.960 116.550 19.065 ;
        RECT 117.300 16.960 117.550 19.065 ;
      LAYER met2 ;
        RECT 98.750 81.930 101.250 81.980 ;
        RECT 66.250 78.380 67.750 79.980 ;
        RECT 98.750 79.430 120.750 81.930 ;
        RECT 98.750 79.380 101.250 79.430 ;
        RECT 95.550 76.480 116.750 76.530 ;
        RECT 95.550 76.130 117.250 76.480 ;
        RECT 95.550 75.180 95.950 76.130 ;
        RECT 116.250 75.880 117.250 76.130 ;
        RECT 69.650 71.330 71.950 71.380 ;
        RECT 76.650 71.330 78.950 71.380 ;
        RECT 83.650 71.330 85.850 74.880 ;
        RECT 90.650 71.330 92.250 74.880 ;
        RECT 94.150 73.180 96.350 75.180 ;
        RECT 118.250 74.930 120.750 79.430 ;
        RECT 98.350 71.330 99.950 74.880 ;
        RECT 104.750 71.330 106.950 74.880 ;
        RECT 111.750 71.430 120.750 74.930 ;
        RECT 111.750 71.330 113.950 71.430 ;
        RECT 69.650 68.730 113.950 71.330 ;
        RECT 119.650 69.480 120.750 71.430 ;
        RECT 69.650 68.680 71.950 68.730 ;
        RECT 76.650 68.680 78.950 68.730 ;
        RECT 68.050 68.430 68.450 68.480 ;
        RECT 73.150 68.430 73.550 68.580 ;
        RECT 74.750 68.430 75.450 68.580 ;
        RECT 80.150 68.430 80.550 68.480 ;
        RECT 68.050 67.730 80.550 68.430 ;
        RECT 83.650 67.980 85.850 68.730 ;
        RECT 90.650 67.880 92.250 68.730 ;
        RECT 98.350 67.880 99.950 68.730 ;
        RECT 104.750 68.680 106.950 68.730 ;
        RECT 111.750 68.680 113.950 68.730 ;
        RECT 101.250 68.330 103.350 68.380 ;
        RECT 108.250 68.330 110.350 68.380 ;
        RECT 115.150 68.330 115.850 68.380 ;
        RECT 68.050 67.680 68.450 67.730 ;
        RECT 73.150 67.480 73.550 67.730 ;
        RECT 74.750 67.480 75.450 67.730 ;
        RECT 80.150 67.680 80.550 67.730 ;
        RECT 101.150 67.630 115.850 68.330 ;
        RECT 101.250 67.580 103.350 67.630 ;
        RECT 108.250 67.580 110.350 67.630 ;
        RECT 115.150 67.580 115.850 67.630 ;
        RECT 116.750 67.380 117.750 69.480 ;
        RECT 119.250 67.430 120.750 69.480 ;
        RECT 119.250 67.380 120.250 67.430 ;
        RECT 96.250 65.830 97.250 65.980 ;
        RECT 98.750 65.830 99.750 65.980 ;
        RECT 96.250 65.530 99.750 65.830 ;
        RECT 96.250 65.380 97.250 65.530 ;
        RECT 96.950 65.330 97.250 65.380 ;
        RECT 98.750 65.380 99.750 65.530 ;
        RECT 98.750 65.330 99.350 65.380 ;
        RECT 77.750 63.930 78.250 63.980 ;
        RECT 80.750 63.930 81.250 64.980 ;
        RECT 88.750 64.930 90.250 64.980 ;
        RECT 93.250 64.930 93.850 64.980 ;
        RECT 118.250 64.930 119.750 64.980 ;
        RECT 88.750 64.430 119.750 64.930 ;
        RECT 88.750 64.380 90.250 64.430 ;
        RECT 93.250 64.380 93.850 64.430 ;
        RECT 118.250 64.380 119.750 64.430 ;
        RECT 77.650 63.430 81.250 63.930 ;
        RECT 77.750 62.880 78.250 63.430 ;
        RECT 80.750 63.380 81.250 63.430 ;
        RECT 114.250 63.930 115.750 63.980 ;
        RECT 118.250 63.930 118.750 63.980 ;
        RECT 114.250 63.430 118.750 63.930 ;
        RECT 114.250 63.380 115.750 63.430 ;
        RECT 116.000 63.010 116.970 63.430 ;
        RECT 118.250 62.380 118.750 63.430 ;
        RECT 92.250 61.230 93.250 61.480 ;
        RECT 100.750 61.230 101.750 61.480 ;
        RECT 92.250 60.930 101.750 61.230 ;
        RECT 92.250 60.880 93.250 60.930 ;
        RECT 100.750 60.880 101.750 60.930 ;
        RECT 71.050 57.930 72.550 58.080 ;
        RECT 74.750 57.930 75.250 58.980 ;
        RECT 77.750 57.930 78.250 58.980 ;
        RECT 106.250 58.930 106.750 58.980 ;
        RECT 94.050 58.430 96.250 58.480 ;
        RECT 71.050 57.430 78.250 57.930 ;
        RECT 71.050 57.380 72.550 57.430 ;
        RECT 74.750 56.880 75.250 57.430 ;
        RECT 77.750 56.880 78.250 57.430 ;
        RECT 93.950 55.530 96.250 58.430 ;
        RECT 106.250 58.430 117.750 58.930 ;
        RECT 106.250 57.880 106.750 58.430 ;
        RECT 108.250 57.930 108.750 57.980 ;
        RECT 108.250 57.430 117.750 57.930 ;
        RECT 108.250 56.880 108.750 57.430 ;
        RECT 115.250 56.930 115.750 56.980 ;
        RECT 115.250 56.430 117.750 56.930 ;
        RECT 115.250 55.880 115.750 56.430 ;
        RECT 66.250 55.330 73.350 55.380 ;
        RECT 76.250 55.330 76.750 55.480 ;
        RECT 94.050 55.330 96.250 55.530 ;
        RECT 116.150 55.330 116.450 55.380 ;
        RECT 66.150 52.430 120.150 55.330 ;
        RECT 66.250 52.380 73.350 52.430 ;
        RECT 74.250 52.380 74.650 52.430 ;
        RECT 76.250 51.880 76.750 52.430 ;
        RECT 91.150 52.380 92.050 52.430 ;
        RECT 94.050 52.380 96.250 52.430 ;
        RECT 83.750 49.930 85.250 49.980 ;
        RECT 108.250 49.930 109.350 49.980 ;
        RECT 83.750 49.430 109.350 49.930 ;
        RECT 83.750 49.380 85.250 49.430 ;
        RECT 108.250 49.380 109.350 49.430 ;
        RECT 110.750 48.930 116.750 52.430 ;
        RECT 112.250 48.880 114.750 48.930 ;
        RECT 78.250 48.430 79.750 48.480 ;
        RECT 106.750 48.430 107.750 48.480 ;
        RECT 78.250 47.930 107.750 48.430 ;
        RECT 78.250 47.880 79.750 47.930 ;
        RECT 106.750 47.880 107.750 47.930 ;
        RECT 108.250 38.430 108.750 39.480 ;
        RECT 110.250 38.430 110.750 38.480 ;
        RECT 108.250 37.930 110.750 38.430 ;
        RECT 108.250 37.880 108.750 37.930 ;
        RECT 90.750 36.430 91.250 36.980 ;
        RECT 110.250 36.880 110.750 37.930 ;
        RECT 116.250 37.930 116.750 37.980 ;
        RECT 120.250 37.930 120.750 37.980 ;
        RECT 116.250 36.430 120.750 37.930 ;
        RECT 90.750 35.930 108.750 36.430 ;
        RECT 116.250 36.380 116.750 36.430 ;
        RECT 120.250 36.380 120.750 36.430 ;
        RECT 90.750 35.380 91.250 35.930 ;
        RECT 108.250 34.930 108.750 35.930 ;
        RECT 110.250 34.930 110.750 35.480 ;
        RECT 108.250 34.430 110.750 34.930 ;
        RECT 108.250 33.880 108.750 34.430 ;
        RECT 110.250 33.880 110.750 34.430 ;
        RECT 110.250 32.430 110.750 32.980 ;
        RECT 119.250 32.430 119.750 33.480 ;
        RECT 110.250 31.930 119.750 32.430 ;
        RECT 110.250 30.880 110.750 31.930 ;
        RECT 119.250 31.880 119.750 31.930 ;
        RECT 97.250 29.430 98.750 29.480 ;
        RECT 112.250 29.430 112.750 29.980 ;
        RECT 97.250 28.930 112.750 29.430 ;
        RECT 97.250 28.880 98.750 28.930 ;
        RECT 112.250 28.380 112.750 28.930 ;
        RECT 112.250 26.930 112.750 27.480 ;
        RECT 117.750 26.930 118.750 26.980 ;
        RECT 112.250 26.430 118.750 26.930 ;
        RECT 100.750 24.430 101.250 25.980 ;
        RECT 112.250 25.880 112.750 26.430 ;
        RECT 117.750 26.380 118.750 26.430 ;
        RECT 116.250 24.430 116.750 24.980 ;
        RECT 100.750 23.930 116.750 24.430 ;
        RECT 100.750 23.880 101.250 23.930 ;
        RECT 116.250 22.880 116.750 23.930 ;
      LAYER met3 ;
        RECT 65.750 80.430 97.610 110.830 ;
        RECT 66.200 78.405 67.800 79.955 ;
        RECT 98.700 79.405 101.300 81.955 ;
        RECT 4.210 73.360 5.660 75.700 ;
        RECT 7.260 72.830 119.830 75.940 ;
        RECT 136.050 63.900 137.050 64.020 ;
        RECT 115.130 63.080 137.080 63.900 ;
        RECT 115.950 63.035 117.020 63.080 ;
        RECT 66.630 54.880 72.950 55.025 ;
        RECT 4.380 54.700 116.950 54.880 ;
        RECT 4.270 52.300 116.950 54.700 ;
        RECT 4.380 51.770 116.950 52.300 ;
        RECT 136.050 0.200 137.050 63.080 ;
      LAYER met4 ;
        RECT 66.145 80.825 95.755 110.435 ;
        RECT 97.110 81.930 97.590 110.770 ;
        RECT 98.745 81.930 101.255 81.935 ;
        RECT 66.250 79.935 67.750 80.825 ;
        RECT 97.110 80.490 101.255 81.930 ;
        RECT 66.245 78.425 67.755 79.935 ;
        RECT 97.250 79.430 101.255 80.490 ;
        RECT 98.745 79.425 101.255 79.430 ;
  END
END tt_um_shimomi_analog
END LIBRARY

